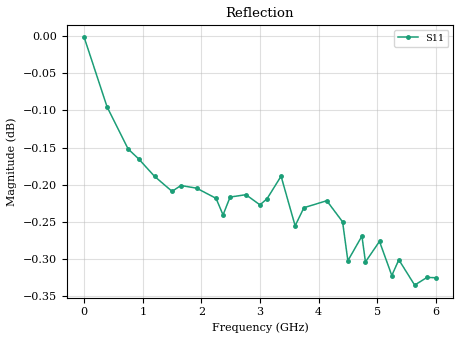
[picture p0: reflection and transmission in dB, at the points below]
! NMT Kit SMA(f) typ SOLT V1 - Short s1p data
! Ref Plane 0 mm
#  MHz  S  RI  R  50
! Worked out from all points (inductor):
!   201 points, 1 MHz to 6.001 GHz, reference 50 ohm
!   read as one part to ground: L = 2.14 nH near 31 MHz
!   highest Q = 41.1 at 3.121 GHz (marker M1), where L = 3.06 nH
!   self-resonance near 5.581 GHz
!   S11 on the Smith chart (normalised r, x): 1 MHz: 0.00, +0.00; 1.201 GHz: 0.01, +0.36; 2.371 GHz: 0.02, +0.79; 3.601 GHz: 0.05, +1.60; 4.801 GHz: 0.35, +4.33; 6.001 GHz: 1.42, -8.54
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1  -0.9998 0.000523
391  -0.9656 0.2144
751  -0.8937 0.4086
931  -0.8468 0.4956
1201  -0.7586 0.6181
1501  -0.6423 0.7352
1651  -0.5778 0.788
1921  -0.4496 0.8671
2251  -0.2841 0.9329
2371  -0.2191 0.9477
2491  -0.1593 0.9623
2761  -0.0169 0.9756
3001  0.1142 0.9675
3121  0.1777 0.9588
3361  0.305 0.9298
3601  0.4277 0.8718
3751  0.4992 0.8361
4141  0.6682 0.7098
4411  0.7642 0.6001
4501  0.7854 0.5621
4741  0.8596 0.4484
4801  0.8688 0.4215
5041  0.9209 0.3006
5251  0.9444 0.1915
5371  0.9577 0.1261
5641  0.9619 -0.0235
5851  0.9538 -0.1352
6001  0.9386 -0.2167
